One B-rep face of a CAD part: STEP entity #844.
In plain terms, the planar face has unit normal (0, -1, 0).
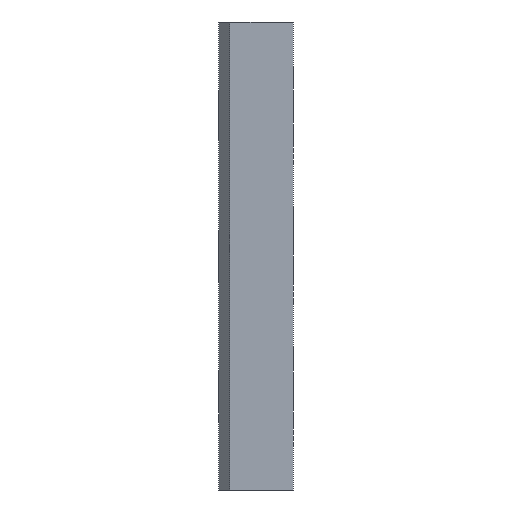
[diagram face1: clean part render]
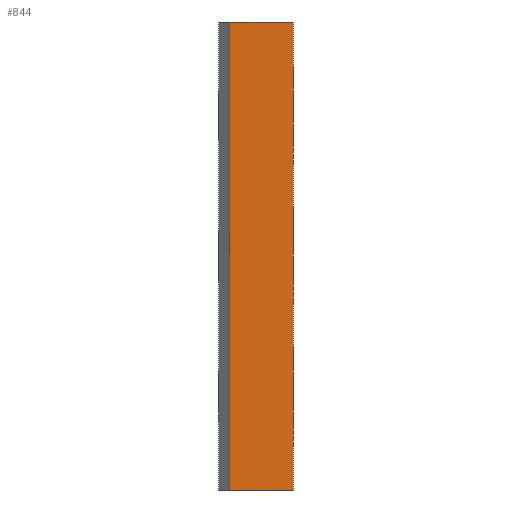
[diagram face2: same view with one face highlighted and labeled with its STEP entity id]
Its self-contained STEP definition (entity closure, numbers rounded to 3 decimals):
#368=CARTESIAN_POINT('Vertex',(20.,0.,-62.5)) ;
#371=CARTESIAN_POINT('Line Origine',(11.5,0.,-62.5)) ;
#375=CARTESIAN_POINT('Vertex',(3.,0.,-62.5)) ;
#398=CARTESIAN_POINT('Line Origine',(3.,0.,0.)) ;
#402=CARTESIAN_POINT('Vertex',(3.,0.,62.5)) ;
#422=CARTESIAN_POINT('Line Origine',(11.5,0.,62.5)) ;
#426=CARTESIAN_POINT('Vertex',(20.,0.,62.5)) ;
#719=CARTESIAN_POINT('Line Origine',(20.,0.,0.)) ;
#833=CARTESIAN_POINT('Axis2P3D Location',(3.,0.,62.5)) ;
#372=DIRECTION('Vector Direction',(1.,0.,0.)) ;
#399=DIRECTION('Vector Direction',(0.,0.,-1.)) ;
#423=DIRECTION('Vector Direction',(1.,0.,0.)) ;
#720=DIRECTION('Vector Direction',(0.,0.,-1.)) ;
#834=DIRECTION('Axis2P3D Direction',(0.,1.,0.)) ;
#835=DIRECTION('Axis2P3D XDirection',(0.,-0.,1.)) ;
#836=AXIS2_PLACEMENT_3D('Plane Axis2P3D',#833,#834,#835) ;
#839=ORIENTED_EDGE('',*,*,#377,.T.) ;
#840=ORIENTED_EDGE('',*,*,#723,.F.) ;
#841=ORIENTED_EDGE('',*,*,#428,.F.) ;
#842=ORIENTED_EDGE('',*,*,#404,.T.) ;
#373=VECTOR('Line Direction',#372,1.) ;
#400=VECTOR('Line Direction',#399,1.) ;
#424=VECTOR('Line Direction',#423,1.) ;
#721=VECTOR('Line Direction',#720,1.) ;
#844=ADVANCED_FACE('A915-125X200',(#843),#837,.F.) ;
#377=EDGE_CURVE('',#376,#369,#374,.T.) ;
#404=EDGE_CURVE('',#403,#376,#401,.T.) ;
#428=EDGE_CURVE('',#403,#427,#425,.T.) ;
#723=EDGE_CURVE('',#427,#369,#722,.T.) ;
#838=EDGE_LOOP('',(#839,#840,#841,#842)) ;
#843=FACE_OUTER_BOUND('',#838,.T.) ;
#374=LINE('Line',#371,#373) ;
#401=LINE('Line',#398,#400) ;
#425=LINE('Line',#422,#424) ;
#722=LINE('Line',#719,#721) ;
#837=PLANE('Plane',#836) ;
#369=VERTEX_POINT('',#368) ;
#376=VERTEX_POINT('',#375) ;
#403=VERTEX_POINT('',#402) ;
#427=VERTEX_POINT('',#426) ;
